VERSION 5.7 ;
BUSBITCHARS "[]" ;
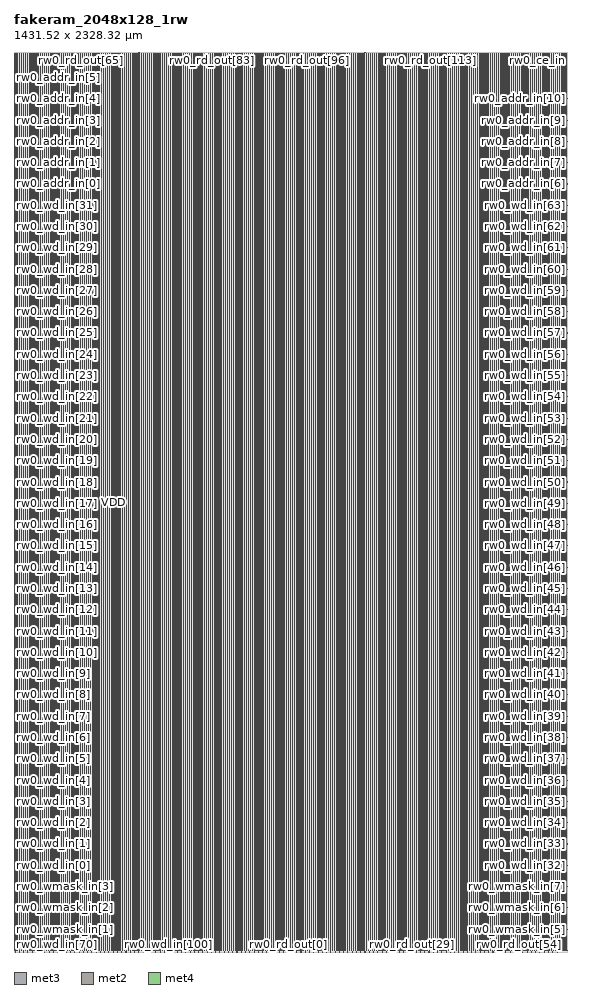
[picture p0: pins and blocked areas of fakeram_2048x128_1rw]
MACRO fakeram_2048x128_1rw
  FOREIGN fakeram_2048x128_1rw 0 0 ;
  SYMMETRY X Y R90 ;
  SIZE 1431.520 BY 2328.320 ;
  CLASS BLOCK ;
  PIN rw0_wmask_in[0]
    DIRECTION INPUT ;
    USE SIGNAL ;
    SHAPE ABUTMENT ;
    PORT
      LAYER met3 ;
      RECT 0.000 3.930 0.900 4.230 ;
    END
  END rw0_wmask_in[0]
  PIN rw0_wmask_in[1]
    DIRECTION INPUT ;
    USE SIGNAL ;
    SHAPE ABUTMENT ;
    PORT
      LAYER met3 ;
      RECT 0.000 59.010 0.900 59.310 ;
    END
  END rw0_wmask_in[1]
  PIN rw0_wmask_in[2]
    DIRECTION INPUT ;
    USE SIGNAL ;
    SHAPE ABUTMENT ;
    PORT
      LAYER met3 ;
      RECT 0.000 114.090 0.900 114.390 ;
    END
  END rw0_wmask_in[2]
  PIN rw0_wmask_in[3]
    DIRECTION INPUT ;
    USE SIGNAL ;
    SHAPE ABUTMENT ;
    PORT
      LAYER met3 ;
      RECT 0.000 169.170 0.900 169.470 ;
    END
  END rw0_wmask_in[3]
  PIN rw0_wmask_in[4]
    DIRECTION INPUT ;
    USE SIGNAL ;
    SHAPE ABUTMENT ;
    PORT
      LAYER met3 ;
      RECT 1430.620 3.930 1431.520 4.230 ;
    END
  END rw0_wmask_in[4]
  PIN rw0_wmask_in[5]
    DIRECTION INPUT ;
    USE SIGNAL ;
    SHAPE ABUTMENT ;
    PORT
      LAYER met3 ;
      RECT 1430.620 59.010 1431.520 59.310 ;
    END
  END rw0_wmask_in[5]
  PIN rw0_wmask_in[6]
    DIRECTION INPUT ;
    USE SIGNAL ;
    SHAPE ABUTMENT ;
    PORT
      LAYER met3 ;
      RECT 1430.620 114.090 1431.520 114.390 ;
    END
  END rw0_wmask_in[6]
  PIN rw0_wmask_in[7]
    DIRECTION INPUT ;
    USE SIGNAL ;
    SHAPE ABUTMENT ;
    PORT
      LAYER met3 ;
      RECT 1430.620 169.170 1431.520 169.470 ;
    END
  END rw0_wmask_in[7]
  PIN rw0_wmask_in[8]
    DIRECTION INPUT ;
    USE SIGNAL ;
    SHAPE ABUTMENT ;
    PORT
      LAYER met2 ;
      RECT 2.690 2327.900 2.830 2328.320 ;
    END
  END rw0_wmask_in[8]
  PIN rw0_wmask_in[9]
    DIRECTION INPUT ;
    USE SIGNAL ;
    SHAPE ABUTMENT ;
    PORT
      LAYER met2 ;
      RECT 21.550 2327.900 21.690 2328.320 ;
    END
  END rw0_wmask_in[9]
  PIN rw0_wmask_in[10]
    DIRECTION INPUT ;
    USE SIGNAL ;
    SHAPE ABUTMENT ;
    PORT
      LAYER met2 ;
      RECT 40.410 2327.900 40.550 2328.320 ;
    END
  END rw0_wmask_in[10]
  PIN rw0_wmask_in[11]
    DIRECTION INPUT ;
    USE SIGNAL ;
    SHAPE ABUTMENT ;
    PORT
      LAYER met2 ;
      RECT 59.270 2327.900 59.410 2328.320 ;
    END
  END rw0_wmask_in[11]
  PIN rw0_wmask_in[12]
    DIRECTION INPUT ;
    USE SIGNAL ;
    SHAPE ABUTMENT ;
    PORT
      LAYER met2 ;
      RECT 78.130 2327.900 78.270 2328.320 ;
    END
  END rw0_wmask_in[12]
  PIN rw0_wmask_in[13]
    DIRECTION INPUT ;
    USE SIGNAL ;
    SHAPE ABUTMENT ;
    PORT
      LAYER met2 ;
      RECT 96.990 2327.900 97.130 2328.320 ;
    END
  END rw0_wmask_in[13]
  PIN rw0_wmask_in[14]
    DIRECTION INPUT ;
    USE SIGNAL ;
    SHAPE ABUTMENT ;
    PORT
      LAYER met2 ;
      RECT 115.850 2327.900 115.990 2328.320 ;
    END
  END rw0_wmask_in[14]
  PIN rw0_wmask_in[15]
    DIRECTION INPUT ;
    USE SIGNAL ;
    SHAPE ABUTMENT ;
    PORT
      LAYER met2 ;
      RECT 134.710 2327.900 134.850 2328.320 ;
    END
  END rw0_wmask_in[15]
  PIN rw0_wd_in[0]
    DIRECTION INPUT ;
    USE SIGNAL ;
    SHAPE ABUTMENT ;
    PORT
      LAYER met3 ;
      RECT 0.000 224.250 0.900 224.550 ;
    END
  END rw0_wd_in[0]
  PIN rw0_wd_in[1]
    DIRECTION INPUT ;
    USE SIGNAL ;
    SHAPE ABUTMENT ;
    PORT
      LAYER met3 ;
      RECT 0.000 279.330 0.900 279.630 ;
    END
  END rw0_wd_in[1]
  PIN rw0_wd_in[2]
    DIRECTION INPUT ;
    USE SIGNAL ;
    SHAPE ABUTMENT ;
    PORT
      LAYER met3 ;
      RECT 0.000 334.410 0.900 334.710 ;
    END
  END rw0_wd_in[2]
  PIN rw0_wd_in[3]
    DIRECTION INPUT ;
    USE SIGNAL ;
    SHAPE ABUTMENT ;
    PORT
      LAYER met3 ;
      RECT 0.000 389.490 0.900 389.790 ;
    END
  END rw0_wd_in[3]
  PIN rw0_wd_in[4]
    DIRECTION INPUT ;
    USE SIGNAL ;
    SHAPE ABUTMENT ;
    PORT
      LAYER met3 ;
      RECT 0.000 444.570 0.900 444.870 ;
    END
  END rw0_wd_in[4]
  PIN rw0_wd_in[5]
    DIRECTION INPUT ;
    USE SIGNAL ;
    SHAPE ABUTMENT ;
    PORT
      LAYER met3 ;
      RECT 0.000 499.650 0.900 499.950 ;
    END
  END rw0_wd_in[5]
  PIN rw0_wd_in[6]
    DIRECTION INPUT ;
    USE SIGNAL ;
    SHAPE ABUTMENT ;
    PORT
      LAYER met3 ;
      RECT 0.000 554.730 0.900 555.030 ;
    END
  END rw0_wd_in[6]
  PIN rw0_wd_in[7]
    DIRECTION INPUT ;
    USE SIGNAL ;
    SHAPE ABUTMENT ;
    PORT
      LAYER met3 ;
      RECT 0.000 609.810 0.900 610.110 ;
    END
  END rw0_wd_in[7]
  PIN rw0_wd_in[8]
    DIRECTION INPUT ;
    USE SIGNAL ;
    SHAPE ABUTMENT ;
    PORT
      LAYER met3 ;
      RECT 0.000 664.890 0.900 665.190 ;
    END
  END rw0_wd_in[8]
  PIN rw0_wd_in[9]
    DIRECTION INPUT ;
    USE SIGNAL ;
    SHAPE ABUTMENT ;
    PORT
      LAYER met3 ;
      RECT 0.000 719.970 0.900 720.270 ;
    END
  END rw0_wd_in[9]
  PIN rw0_wd_in[10]
    DIRECTION INPUT ;
    USE SIGNAL ;
    SHAPE ABUTMENT ;
    PORT
      LAYER met3 ;
      RECT 0.000 775.050 0.900 775.350 ;
    END
  END rw0_wd_in[10]
  PIN rw0_wd_in[11]
    DIRECTION INPUT ;
    USE SIGNAL ;
    SHAPE ABUTMENT ;
    PORT
      LAYER met3 ;
      RECT 0.000 830.130 0.900 830.430 ;
    END
  END rw0_wd_in[11]
  PIN rw0_wd_in[12]
    DIRECTION INPUT ;
    USE SIGNAL ;
    SHAPE ABUTMENT ;
    PORT
      LAYER met3 ;
      RECT 0.000 885.210 0.900 885.510 ;
    END
  END rw0_wd_in[12]
  PIN rw0_wd_in[13]
    DIRECTION INPUT ;
    USE SIGNAL ;
    SHAPE ABUTMENT ;
    PORT
      LAYER met3 ;
      RECT 0.000 940.290 0.900 940.590 ;
    END
  END rw0_wd_in[13]
  PIN rw0_wd_in[14]
    DIRECTION INPUT ;
    USE SIGNAL ;
    SHAPE ABUTMENT ;
    PORT
      LAYER met3 ;
      RECT 0.000 995.370 0.900 995.670 ;
    END
  END rw0_wd_in[14]
  PIN rw0_wd_in[15]
    DIRECTION INPUT ;
    USE SIGNAL ;
    SHAPE ABUTMENT ;
    PORT
      LAYER met3 ;
      RECT 0.000 1050.450 0.900 1050.750 ;
    END
  END rw0_wd_in[15]
  PIN rw0_wd_in[16]
    DIRECTION INPUT ;
    USE SIGNAL ;
    SHAPE ABUTMENT ;
    PORT
      LAYER met3 ;
      RECT 0.000 1105.530 0.900 1105.830 ;
    END
  END rw0_wd_in[16]
  PIN rw0_wd_in[17]
    DIRECTION INPUT ;
    USE SIGNAL ;
    SHAPE ABUTMENT ;
    PORT
      LAYER met3 ;
      RECT 0.000 1160.610 0.900 1160.910 ;
    END
  END rw0_wd_in[17]
  PIN rw0_wd_in[18]
    DIRECTION INPUT ;
    USE SIGNAL ;
    SHAPE ABUTMENT ;
    PORT
      LAYER met3 ;
      RECT 0.000 1215.690 0.900 1215.990 ;
    END
  END rw0_wd_in[18]
  PIN rw0_wd_in[19]
    DIRECTION INPUT ;
    USE SIGNAL ;
    SHAPE ABUTMENT ;
    PORT
      LAYER met3 ;
      RECT 0.000 1270.770 0.900 1271.070 ;
    END
  END rw0_wd_in[19]
  PIN rw0_wd_in[20]
    DIRECTION INPUT ;
    USE SIGNAL ;
    SHAPE ABUTMENT ;
    PORT
      LAYER met3 ;
      RECT 0.000 1325.850 0.900 1326.150 ;
    END
  END rw0_wd_in[20]
  PIN rw0_wd_in[21]
    DIRECTION INPUT ;
    USE SIGNAL ;
    SHAPE ABUTMENT ;
    PORT
      LAYER met3 ;
      RECT 0.000 1380.930 0.900 1381.230 ;
    END
  END rw0_wd_in[21]
  PIN rw0_wd_in[22]
    DIRECTION INPUT ;
    USE SIGNAL ;
    SHAPE ABUTMENT ;
    PORT
      LAYER met3 ;
      RECT 0.000 1436.010 0.900 1436.310 ;
    END
  END rw0_wd_in[22]
  PIN rw0_wd_in[23]
    DIRECTION INPUT ;
    USE SIGNAL ;
    SHAPE ABUTMENT ;
    PORT
      LAYER met3 ;
      RECT 0.000 1491.090 0.900 1491.390 ;
    END
  END rw0_wd_in[23]
  PIN rw0_wd_in[24]
    DIRECTION INPUT ;
    USE SIGNAL ;
    SHAPE ABUTMENT ;
    PORT
      LAYER met3 ;
      RECT 0.000 1546.170 0.900 1546.470 ;
    END
  END rw0_wd_in[24]
  PIN rw0_wd_in[25]
    DIRECTION INPUT ;
    USE SIGNAL ;
    SHAPE ABUTMENT ;
    PORT
      LAYER met3 ;
      RECT 0.000 1601.250 0.900 1601.550 ;
    END
  END rw0_wd_in[25]
  PIN rw0_wd_in[26]
    DIRECTION INPUT ;
    USE SIGNAL ;
    SHAPE ABUTMENT ;
    PORT
      LAYER met3 ;
      RECT 0.000 1656.330 0.900 1656.630 ;
    END
  END rw0_wd_in[26]
  PIN rw0_wd_in[27]
    DIRECTION INPUT ;
    USE SIGNAL ;
    SHAPE ABUTMENT ;
    PORT
      LAYER met3 ;
      RECT 0.000 1711.410 0.900 1711.710 ;
    END
  END rw0_wd_in[27]
  PIN rw0_wd_in[28]
    DIRECTION INPUT ;
    USE SIGNAL ;
    SHAPE ABUTMENT ;
    PORT
      LAYER met3 ;
      RECT 0.000 1766.490 0.900 1766.790 ;
    END
  END rw0_wd_in[28]
  PIN rw0_wd_in[29]
    DIRECTION INPUT ;
    USE SIGNAL ;
    SHAPE ABUTMENT ;
    PORT
      LAYER met3 ;
      RECT 0.000 1821.570 0.900 1821.870 ;
    END
  END rw0_wd_in[29]
  PIN rw0_wd_in[30]
    DIRECTION INPUT ;
    USE SIGNAL ;
    SHAPE ABUTMENT ;
    PORT
      LAYER met3 ;
      RECT 0.000 1876.650 0.900 1876.950 ;
    END
  END rw0_wd_in[30]
  PIN rw0_wd_in[31]
    DIRECTION INPUT ;
    USE SIGNAL ;
    SHAPE ABUTMENT ;
    PORT
      LAYER met3 ;
      RECT 0.000 1931.730 0.900 1932.030 ;
    END
  END rw0_wd_in[31]
  PIN rw0_wd_in[32]
    DIRECTION INPUT ;
    USE SIGNAL ;
    SHAPE ABUTMENT ;
    PORT
      LAYER met3 ;
      RECT 1430.620 224.250 1431.520 224.550 ;
    END
  END rw0_wd_in[32]
  PIN rw0_wd_in[33]
    DIRECTION INPUT ;
    USE SIGNAL ;
    SHAPE ABUTMENT ;
    PORT
      LAYER met3 ;
      RECT 1430.620 279.330 1431.520 279.630 ;
    END
  END rw0_wd_in[33]
  PIN rw0_wd_in[34]
    DIRECTION INPUT ;
    USE SIGNAL ;
    SHAPE ABUTMENT ;
    PORT
      LAYER met3 ;
      RECT 1430.620 334.410 1431.520 334.710 ;
    END
  END rw0_wd_in[34]
  PIN rw0_wd_in[35]
    DIRECTION INPUT ;
    USE SIGNAL ;
    SHAPE ABUTMENT ;
    PORT
      LAYER met3 ;
      RECT 1430.620 389.490 1431.520 389.790 ;
    END
  END rw0_wd_in[35]
  PIN rw0_wd_in[36]
    DIRECTION INPUT ;
    USE SIGNAL ;
    SHAPE ABUTMENT ;
    PORT
      LAYER met3 ;
      RECT 1430.620 444.570 1431.520 444.870 ;
    END
  END rw0_wd_in[36]
  PIN rw0_wd_in[37]
    DIRECTION INPUT ;
    USE SIGNAL ;
    SHAPE ABUTMENT ;
    PORT
      LAYER met3 ;
      RECT 1430.620 499.650 1431.520 499.950 ;
    END
  END rw0_wd_in[37]
  PIN rw0_wd_in[38]
    DIRECTION INPUT ;
    USE SIGNAL ;
    SHAPE ABUTMENT ;
    PORT
      LAYER met3 ;
      RECT 1430.620 554.730 1431.520 555.030 ;
    END
  END rw0_wd_in[38]
  PIN rw0_wd_in[39]
    DIRECTION INPUT ;
    USE SIGNAL ;
    SHAPE ABUTMENT ;
    PORT
      LAYER met3 ;
      RECT 1430.620 609.810 1431.520 610.110 ;
    END
  END rw0_wd_in[39]
  PIN rw0_wd_in[40]
    DIRECTION INPUT ;
    USE SIGNAL ;
    SHAPE ABUTMENT ;
    PORT
      LAYER met3 ;
      RECT 1430.620 664.890 1431.520 665.190 ;
    END
  END rw0_wd_in[40]
  PIN rw0_wd_in[41]
    DIRECTION INPUT ;
    USE SIGNAL ;
    SHAPE ABUTMENT ;
    PORT
      LAYER met3 ;
      RECT 1430.620 719.970 1431.520 720.270 ;
    END
  END rw0_wd_in[41]
  PIN rw0_wd_in[42]
    DIRECTION INPUT ;
    USE SIGNAL ;
    SHAPE ABUTMENT ;
    PORT
      LAYER met3 ;
      RECT 1430.620 775.050 1431.520 775.350 ;
    END
  END rw0_wd_in[42]
  PIN rw0_wd_in[43]
    DIRECTION INPUT ;
    USE SIGNAL ;
    SHAPE ABUTMENT ;
    PORT
      LAYER met3 ;
      RECT 1430.620 830.130 1431.520 830.430 ;
    END
  END rw0_wd_in[43]
  PIN rw0_wd_in[44]
    DIRECTION INPUT ;
    USE SIGNAL ;
    SHAPE ABUTMENT ;
    PORT
      LAYER met3 ;
      RECT 1430.620 885.210 1431.520 885.510 ;
    END
  END rw0_wd_in[44]
  PIN rw0_wd_in[45]
    DIRECTION INPUT ;
    USE SIGNAL ;
    SHAPE ABUTMENT ;
    PORT
      LAYER met3 ;
      RECT 1430.620 940.290 1431.520 940.590 ;
    END
  END rw0_wd_in[45]
  PIN rw0_wd_in[46]
    DIRECTION INPUT ;
    USE SIGNAL ;
    SHAPE ABUTMENT ;
    PORT
      LAYER met3 ;
      RECT 1430.620 995.370 1431.520 995.670 ;
    END
  END rw0_wd_in[46]
  PIN rw0_wd_in[47]
    DIRECTION INPUT ;
    USE SIGNAL ;
    SHAPE ABUTMENT ;
    PORT
      LAYER met3 ;
      RECT 1430.620 1050.450 1431.520 1050.750 ;
    END
  END rw0_wd_in[47]
  PIN rw0_wd_in[48]
    DIRECTION INPUT ;
    USE SIGNAL ;
    SHAPE ABUTMENT ;
    PORT
      LAYER met3 ;
      RECT 1430.620 1105.530 1431.520 1105.830 ;
    END
  END rw0_wd_in[48]
  PIN rw0_wd_in[49]
    DIRECTION INPUT ;
    USE SIGNAL ;
    SHAPE ABUTMENT ;
    PORT
      LAYER met3 ;
      RECT 1430.620 1160.610 1431.520 1160.910 ;
    END
  END rw0_wd_in[49]
  PIN rw0_wd_in[50]
    DIRECTION INPUT ;
    USE SIGNAL ;
    SHAPE ABUTMENT ;
    PORT
      LAYER met3 ;
      RECT 1430.620 1215.690 1431.520 1215.990 ;
    END
  END rw0_wd_in[50]
  PIN rw0_wd_in[51]
    DIRECTION INPUT ;
    USE SIGNAL ;
    SHAPE ABUTMENT ;
    PORT
      LAYER met3 ;
      RECT 1430.620 1270.770 1431.520 1271.070 ;
    END
  END rw0_wd_in[51]
  PIN rw0_wd_in[52]
    DIRECTION INPUT ;
    USE SIGNAL ;
    SHAPE ABUTMENT ;
    PORT
      LAYER met3 ;
      RECT 1430.620 1325.850 1431.520 1326.150 ;
    END
  END rw0_wd_in[52]
  PIN rw0_wd_in[53]
    DIRECTION INPUT ;
    USE SIGNAL ;
    SHAPE ABUTMENT ;
    PORT
      LAYER met3 ;
      RECT 1430.620 1380.930 1431.520 1381.230 ;
    END
  END rw0_wd_in[53]
  PIN rw0_wd_in[54]
    DIRECTION INPUT ;
    USE SIGNAL ;
    SHAPE ABUTMENT ;
    PORT
      LAYER met3 ;
      RECT 1430.620 1436.010 1431.520 1436.310 ;
    END
  END rw0_wd_in[54]
  PIN rw0_wd_in[55]
    DIRECTION INPUT ;
    USE SIGNAL ;
    SHAPE ABUTMENT ;
    PORT
      LAYER met3 ;
      RECT 1430.620 1491.090 1431.520 1491.390 ;
    END
  END rw0_wd_in[55]
  PIN rw0_wd_in[56]
    DIRECTION INPUT ;
    USE SIGNAL ;
    SHAPE ABUTMENT ;
    PORT
      LAYER met3 ;
      RECT 1430.620 1546.170 1431.520 1546.470 ;
    END
  END rw0_wd_in[56]
  PIN rw0_wd_in[57]
    DIRECTION INPUT ;
    USE SIGNAL ;
    SHAPE ABUTMENT ;
    PORT
      LAYER met3 ;
      RECT 1430.620 1601.250 1431.520 1601.550 ;
    END
  END rw0_wd_in[57]
  PIN rw0_wd_in[58]
    DIRECTION INPUT ;
    USE SIGNAL ;
    SHAPE ABUTMENT ;
    PORT
      LAYER met3 ;
      RECT 1430.620 1656.330 1431.520 1656.630 ;
    END
  END rw0_wd_in[58]
  PIN rw0_wd_in[59]
    DIRECTION INPUT ;
    USE SIGNAL ;
    SHAPE ABUTMENT ;
    PORT
      LAYER met3 ;
      RECT 1430.620 1711.410 1431.520 1711.710 ;
    END
  END rw0_wd_in[59]
  PIN rw0_wd_in[60]
    DIRECTION INPUT ;
    USE SIGNAL ;
    SHAPE ABUTMENT ;
    PORT
      LAYER met3 ;
      RECT 1430.620 1766.490 1431.520 1766.790 ;
    END
  END rw0_wd_in[60]
  PIN rw0_wd_in[61]
    DIRECTION INPUT ;
    USE SIGNAL ;
    SHAPE ABUTMENT ;
    PORT
      LAYER met3 ;
      RECT 1430.620 1821.570 1431.520 1821.870 ;
    END
  END rw0_wd_in[61]
  PIN rw0_wd_in[62]
    DIRECTION INPUT ;
    USE SIGNAL ;
    SHAPE ABUTMENT ;
    PORT
      LAYER met3 ;
      RECT 1430.620 1876.650 1431.520 1876.950 ;
    END
  END rw0_wd_in[62]
  PIN rw0_wd_in[63]
    DIRECTION INPUT ;
    USE SIGNAL ;
    SHAPE ABUTMENT ;
    PORT
      LAYER met3 ;
      RECT 1430.620 1931.730 1431.520 1932.030 ;
    END
  END rw0_wd_in[63]
  PIN rw0_wd_in[64]
    DIRECTION INPUT ;
    USE SIGNAL ;
    SHAPE ABUTMENT ;
    PORT
      LAYER met2 ;
      RECT 2.690 0.000 2.830 0.420 ;
    END
  END rw0_wd_in[64]
  PIN rw0_wd_in[65]
    DIRECTION INPUT ;
    USE SIGNAL ;
    SHAPE ABUTMENT ;
    PORT
      LAYER met2 ;
      RECT 13.730 0.000 13.870 0.420 ;
    END
  END rw0_wd_in[65]
  PIN rw0_wd_in[66]
    DIRECTION INPUT ;
    USE SIGNAL ;
    SHAPE ABUTMENT ;
    PORT
      LAYER met2 ;
      RECT 24.770 0.000 24.910 0.420 ;
    END
  END rw0_wd_in[66]
  PIN rw0_wd_in[67]
    DIRECTION INPUT ;
    USE SIGNAL ;
    SHAPE ABUTMENT ;
    PORT
      LAYER met2 ;
      RECT 35.810 0.000 35.950 0.420 ;
    END
  END rw0_wd_in[67]
  PIN rw0_wd_in[68]
    DIRECTION INPUT ;
    USE SIGNAL ;
    SHAPE ABUTMENT ;
    PORT
      LAYER met2 ;
      RECT 46.850 0.000 46.990 0.420 ;
    END
  END rw0_wd_in[68]
  PIN rw0_wd_in[69]
    DIRECTION INPUT ;
    USE SIGNAL ;
    SHAPE ABUTMENT ;
    PORT
      LAYER met2 ;
      RECT 57.890 0.000 58.030 0.420 ;
    END
  END rw0_wd_in[69]
  PIN rw0_wd_in[70]
    DIRECTION INPUT ;
    USE SIGNAL ;
    SHAPE ABUTMENT ;
    PORT
      LAYER met2 ;
      RECT 68.930 0.000 69.070 0.420 ;
    END
  END rw0_wd_in[70]
  PIN rw0_wd_in[71]
    DIRECTION INPUT ;
    USE SIGNAL ;
    SHAPE ABUTMENT ;
    PORT
      LAYER met2 ;
      RECT 79.970 0.000 80.110 0.420 ;
    END
  END rw0_wd_in[71]
  PIN rw0_wd_in[72]
    DIRECTION INPUT ;
    USE SIGNAL ;
    SHAPE ABUTMENT ;
    PORT
      LAYER met2 ;
      RECT 91.010 0.000 91.150 0.420 ;
    END
  END rw0_wd_in[72]
  PIN rw0_wd_in[73]
    DIRECTION INPUT ;
    USE SIGNAL ;
    SHAPE ABUTMENT ;
    PORT
      LAYER met2 ;
      RECT 102.050 0.000 102.190 0.420 ;
    END
  END rw0_wd_in[73]
  PIN rw0_wd_in[74]
    DIRECTION INPUT ;
    USE SIGNAL ;
    SHAPE ABUTMENT ;
    PORT
      LAYER met2 ;
      RECT 113.090 0.000 113.230 0.420 ;
    END
  END rw0_wd_in[74]
  PIN rw0_wd_in[75]
    DIRECTION INPUT ;
    USE SIGNAL ;
    SHAPE ABUTMENT ;
    PORT
      LAYER met2 ;
      RECT 124.130 0.000 124.270 0.420 ;
    END
  END rw0_wd_in[75]
  PIN rw0_wd_in[76]
    DIRECTION INPUT ;
    USE SIGNAL ;
    SHAPE ABUTMENT ;
    PORT
      LAYER met2 ;
      RECT 135.170 0.000 135.310 0.420 ;
    END
  END rw0_wd_in[76]
  PIN rw0_wd_in[77]
    DIRECTION INPUT ;
    USE SIGNAL ;
    SHAPE ABUTMENT ;
    PORT
      LAYER met2 ;
      RECT 146.210 0.000 146.350 0.420 ;
    END
  END rw0_wd_in[77]
  PIN rw0_wd_in[78]
    DIRECTION INPUT ;
    USE SIGNAL ;
    SHAPE ABUTMENT ;
    PORT
      LAYER met2 ;
      RECT 157.250 0.000 157.390 0.420 ;
    END
  END rw0_wd_in[78]
  PIN rw0_wd_in[79]
    DIRECTION INPUT ;
    USE SIGNAL ;
    SHAPE ABUTMENT ;
    PORT
      LAYER met2 ;
      RECT 168.290 0.000 168.430 0.420 ;
    END
  END rw0_wd_in[79]
  PIN rw0_wd_in[80]
    DIRECTION INPUT ;
    USE SIGNAL ;
    SHAPE ABUTMENT ;
    PORT
      LAYER met2 ;
      RECT 179.330 0.000 179.470 0.420 ;
    END
  END rw0_wd_in[80]
  PIN rw0_wd_in[81]
    DIRECTION INPUT ;
    USE SIGNAL ;
    SHAPE ABUTMENT ;
    PORT
      LAYER met2 ;
      RECT 190.370 0.000 190.510 0.420 ;
    END
  END rw0_wd_in[81]
  PIN rw0_wd_in[82]
    DIRECTION INPUT ;
    USE SIGNAL ;
    SHAPE ABUTMENT ;
    PORT
      LAYER met2 ;
      RECT 201.410 0.000 201.550 0.420 ;
    END
  END rw0_wd_in[82]
  PIN rw0_wd_in[83]
    DIRECTION INPUT ;
    USE SIGNAL ;
    SHAPE ABUTMENT ;
    PORT
      LAYER met2 ;
      RECT 212.450 0.000 212.590 0.420 ;
    END
  END rw0_wd_in[83]
  PIN rw0_wd_in[84]
    DIRECTION INPUT ;
    USE SIGNAL ;
    SHAPE ABUTMENT ;
    PORT
      LAYER met2 ;
      RECT 223.490 0.000 223.630 0.420 ;
    END
  END rw0_wd_in[84]
  PIN rw0_wd_in[85]
    DIRECTION INPUT ;
    USE SIGNAL ;
    SHAPE ABUTMENT ;
    PORT
      LAYER met2 ;
      RECT 234.530 0.000 234.670 0.420 ;
    END
  END rw0_wd_in[85]
  PIN rw0_wd_in[86]
    DIRECTION INPUT ;
    USE SIGNAL ;
    SHAPE ABUTMENT ;
    PORT
      LAYER met2 ;
      RECT 245.570 0.000 245.710 0.420 ;
    END
  END rw0_wd_in[86]
  PIN rw0_wd_in[87]
    DIRECTION INPUT ;
    USE SIGNAL ;
    SHAPE ABUTMENT ;
    PORT
      LAYER met2 ;
      RECT 256.610 0.000 256.750 0.420 ;
    END
  END rw0_wd_in[87]
  PIN rw0_wd_in[88]
    DIRECTION INPUT ;
    USE SIGNAL ;
    SHAPE ABUTMENT ;
    PORT
      LAYER met2 ;
      RECT 267.650 0.000 267.790 0.420 ;
    END
  END rw0_wd_in[88]
  PIN rw0_wd_in[89]
    DIRECTION INPUT ;
    USE SIGNAL ;
    SHAPE ABUTMENT ;
    PORT
      LAYER met2 ;
      RECT 278.690 0.000 278.830 0.420 ;
    END
  END rw0_wd_in[89]
  PIN rw0_wd_in[90]
    DIRECTION INPUT ;
    USE SIGNAL ;
    SHAPE ABUTMENT ;
    PORT
      LAYER met2 ;
      RECT 289.730 0.000 289.870 0.420 ;
    END
  END rw0_wd_in[90]
  PIN rw0_wd_in[91]
    DIRECTION INPUT ;
    USE SIGNAL ;
    SHAPE ABUTMENT ;
    PORT
      LAYER met2 ;
      RECT 300.770 0.000 300.910 0.420 ;
    END
  END rw0_wd_in[91]
  PIN rw0_wd_in[92]
    DIRECTION INPUT ;
    USE SIGNAL ;
    SHAPE ABUTMENT ;
    PORT
      LAYER met2 ;
      RECT 311.810 0.000 311.950 0.420 ;
    END
  END rw0_wd_in[92]
  PIN rw0_wd_in[93]
    DIRECTION INPUT ;
    USE SIGNAL ;
    SHAPE ABUTMENT ;
    PORT
      LAYER met2 ;
      RECT 322.850 0.000 322.990 0.420 ;
    END
  END rw0_wd_in[93]
  PIN rw0_wd_in[94]
    DIRECTION INPUT ;
    USE SIGNAL ;
    SHAPE ABUTMENT ;
    PORT
      LAYER met2 ;
      RECT 333.890 0.000 334.030 0.420 ;
    END
  END rw0_wd_in[94]
  PIN rw0_wd_in[95]
    DIRECTION INPUT ;
    USE SIGNAL ;
    SHAPE ABUTMENT ;
    PORT
      LAYER met2 ;
      RECT 344.930 0.000 345.070 0.420 ;
    END
  END rw0_wd_in[95]
  PIN rw0_wd_in[96]
    DIRECTION INPUT ;
    USE SIGNAL ;
    SHAPE ABUTMENT ;
    PORT
      LAYER met2 ;
      RECT 355.970 0.000 356.110 0.420 ;
    END
  END rw0_wd_in[96]
  PIN rw0_wd_in[97]
    DIRECTION INPUT ;
    USE SIGNAL ;
    SHAPE ABUTMENT ;
    PORT
      LAYER met2 ;
      RECT 367.010 0.000 367.150 0.420 ;
    END
  END rw0_wd_in[97]
  PIN rw0_wd_in[98]
    DIRECTION INPUT ;
    USE SIGNAL ;
    SHAPE ABUTMENT ;
    PORT
      LAYER met2 ;
      RECT 378.050 0.000 378.190 0.420 ;
    END
  END rw0_wd_in[98]
  PIN rw0_wd_in[99]
    DIRECTION INPUT ;
    USE SIGNAL ;
    SHAPE ABUTMENT ;
    PORT
      LAYER met2 ;
      RECT 389.090 0.000 389.230 0.420 ;
    END
  END rw0_wd_in[99]
  PIN rw0_wd_in[100]
    DIRECTION INPUT ;
    USE SIGNAL ;
    SHAPE ABUTMENT ;
    PORT
      LAYER met2 ;
      RECT 400.130 0.000 400.270 0.420 ;
    END
  END rw0_wd_in[100]
  PIN rw0_wd_in[101]
    DIRECTION INPUT ;
    USE SIGNAL ;
    SHAPE ABUTMENT ;
    PORT
      LAYER met2 ;
      RECT 411.170 0.000 411.310 0.420 ;
    END
  END rw0_wd_in[101]
  PIN rw0_wd_in[102]
    DIRECTION INPUT ;
    USE SIGNAL ;
    SHAPE ABUTMENT ;
    PORT
      LAYER met2 ;
      RECT 422.210 0.000 422.350 0.420 ;
    END
  END rw0_wd_in[102]
  PIN rw0_wd_in[103]
    DIRECTION INPUT ;
    USE SIGNAL ;
    SHAPE ABUTMENT ;
    PORT
      LAYER met2 ;
      RECT 433.250 0.000 433.390 0.420 ;
    END
  END rw0_wd_in[103]
  PIN rw0_wd_in[104]
    DIRECTION INPUT ;
    USE SIGNAL ;
    SHAPE ABUTMENT ;
    PORT
      LAYER met2 ;
      RECT 444.290 0.000 444.430 0.420 ;
    END
  END rw0_wd_in[104]
  PIN rw0_wd_in[105]
    DIRECTION INPUT ;
    USE SIGNAL ;
    SHAPE ABUTMENT ;
    PORT
      LAYER met2 ;
      RECT 455.330 0.000 455.470 0.420 ;
    END
  END rw0_wd_in[105]
  PIN rw0_wd_in[106]
    DIRECTION INPUT ;
    USE SIGNAL ;
    SHAPE ABUTMENT ;
    PORT
      LAYER met2 ;
      RECT 466.370 0.000 466.510 0.420 ;
    END
  END rw0_wd_in[106]
  PIN rw0_wd_in[107]
    DIRECTION INPUT ;
    USE SIGNAL ;
    SHAPE ABUTMENT ;
    PORT
      LAYER met2 ;
      RECT 477.410 0.000 477.550 0.420 ;
    END
  END rw0_wd_in[107]
  PIN rw0_wd_in[108]
    DIRECTION INPUT ;
    USE SIGNAL ;
    SHAPE ABUTMENT ;
    PORT
      LAYER met2 ;
      RECT 488.450 0.000 488.590 0.420 ;
    END
  END rw0_wd_in[108]
  PIN rw0_wd_in[109]
    DIRECTION INPUT ;
    USE SIGNAL ;
    SHAPE ABUTMENT ;
    PORT
      LAYER met2 ;
      RECT 499.490 0.000 499.630 0.420 ;
    END
  END rw0_wd_in[109]
  PIN rw0_wd_in[110]
    DIRECTION INPUT ;
    USE SIGNAL ;
    SHAPE ABUTMENT ;
    PORT
      LAYER met2 ;
      RECT 510.530 0.000 510.670 0.420 ;
    END
  END rw0_wd_in[110]
  PIN rw0_wd_in[111]
    DIRECTION INPUT ;
    USE SIGNAL ;
    SHAPE ABUTMENT ;
    PORT
      LAYER met2 ;
      RECT 521.570 0.000 521.710 0.420 ;
    END
  END rw0_wd_in[111]
  PIN rw0_wd_in[112]
    DIRECTION INPUT ;
    USE SIGNAL ;
    SHAPE ABUTMENT ;
    PORT
      LAYER met2 ;
      RECT 532.610 0.000 532.750 0.420 ;
    END
  END rw0_wd_in[112]
  PIN rw0_wd_in[113]
    DIRECTION INPUT ;
    USE SIGNAL ;
    SHAPE ABUTMENT ;
    PORT
      LAYER met2 ;
      RECT 543.650 0.000 543.790 0.420 ;
    END
  END rw0_wd_in[113]
  PIN rw0_wd_in[114]
    DIRECTION INPUT ;
    USE SIGNAL ;
    SHAPE ABUTMENT ;
    PORT
      LAYER met2 ;
      RECT 554.690 0.000 554.830 0.420 ;
    END
  END rw0_wd_in[114]
  PIN rw0_wd_in[115]
    DIRECTION INPUT ;
    USE SIGNAL ;
    SHAPE ABUTMENT ;
    PORT
      LAYER met2 ;
      RECT 565.730 0.000 565.870 0.420 ;
    END
  END rw0_wd_in[115]
  PIN rw0_wd_in[116]
    DIRECTION INPUT ;
    USE SIGNAL ;
    SHAPE ABUTMENT ;
    PORT
      LAYER met2 ;
      RECT 576.770 0.000 576.910 0.420 ;
    END
  END rw0_wd_in[116]
  PIN rw0_wd_in[117]
    DIRECTION INPUT ;
    USE SIGNAL ;
    SHAPE ABUTMENT ;
    PORT
      LAYER met2 ;
      RECT 587.810 0.000 587.950 0.420 ;
    END
  END rw0_wd_in[117]
  PIN rw0_wd_in[118]
    DIRECTION INPUT ;
    USE SIGNAL ;
    SHAPE ABUTMENT ;
    PORT
      LAYER met2 ;
      RECT 598.850 0.000 598.990 0.420 ;
    END
  END rw0_wd_in[118]
  PIN rw0_wd_in[119]
    DIRECTION INPUT ;
    USE SIGNAL ;
    SHAPE ABUTMENT ;
    PORT
      LAYER met2 ;
      RECT 609.890 0.000 610.030 0.420 ;
    END
  END rw0_wd_in[119]
  PIN rw0_wd_in[120]
    DIRECTION INPUT ;
    USE SIGNAL ;
    SHAPE ABUTMENT ;
    PORT
      LAYER met2 ;
      RECT 620.930 0.000 621.070 0.420 ;
    END
  END rw0_wd_in[120]
  PIN rw0_wd_in[121]
    DIRECTION INPUT ;
    USE SIGNAL ;
    SHAPE ABUTMENT ;
    PORT
      LAYER met2 ;
      RECT 631.970 0.000 632.110 0.420 ;
    END
  END rw0_wd_in[121]
  PIN rw0_wd_in[122]
    DIRECTION INPUT ;
    USE SIGNAL ;
    SHAPE ABUTMENT ;
    PORT
      LAYER met2 ;
      RECT 643.010 0.000 643.150 0.420 ;
    END
  END rw0_wd_in[122]
  PIN rw0_wd_in[123]
    DIRECTION INPUT ;
    USE SIGNAL ;
    SHAPE ABUTMENT ;
    PORT
      LAYER met2 ;
      RECT 654.050 0.000 654.190 0.420 ;
    END
  END rw0_wd_in[123]
  PIN rw0_wd_in[124]
    DIRECTION INPUT ;
    USE SIGNAL ;
    SHAPE ABUTMENT ;
    PORT
      LAYER met2 ;
      RECT 665.090 0.000 665.230 0.420 ;
    END
  END rw0_wd_in[124]
  PIN rw0_wd_in[125]
    DIRECTION INPUT ;
    USE SIGNAL ;
    SHAPE ABUTMENT ;
    PORT
      LAYER met2 ;
      RECT 676.130 0.000 676.270 0.420 ;
    END
  END rw0_wd_in[125]
  PIN rw0_wd_in[126]
    DIRECTION INPUT ;
    USE SIGNAL ;
    SHAPE ABUTMENT ;
    PORT
      LAYER met2 ;
      RECT 687.170 0.000 687.310 0.420 ;
    END
  END rw0_wd_in[126]
  PIN rw0_wd_in[127]
    DIRECTION INPUT ;
    USE SIGNAL ;
    SHAPE ABUTMENT ;
    PORT
      LAYER met2 ;
      RECT 698.210 0.000 698.350 0.420 ;
    END
  END rw0_wd_in[127]
  PIN rw0_rd_out[0]
    DIRECTION OUTPUT ;
    USE SIGNAL ;
    SHAPE ABUTMENT ;
    PORT
      LAYER met2 ;
      RECT 709.250 0.000 709.390 0.420 ;
    END
  END rw0_rd_out[0]
  PIN rw0_rd_out[1]
    DIRECTION OUTPUT ;
    USE SIGNAL ;
    SHAPE ABUTMENT ;
    PORT
      LAYER met2 ;
      RECT 720.290 0.000 720.430 0.420 ;
    END
  END rw0_rd_out[1]
  PIN rw0_rd_out[2]
    DIRECTION OUTPUT ;
    USE SIGNAL ;
    SHAPE ABUTMENT ;
    PORT
      LAYER met2 ;
      RECT 731.330 0.000 731.470 0.420 ;
    END
  END rw0_rd_out[2]
  PIN rw0_rd_out[3]
    DIRECTION OUTPUT ;
    USE SIGNAL ;
    SHAPE ABUTMENT ;
    PORT
      LAYER met2 ;
      RECT 742.370 0.000 742.510 0.420 ;
    END
  END rw0_rd_out[3]
  PIN rw0_rd_out[4]
    DIRECTION OUTPUT ;
    USE SIGNAL ;
    SHAPE ABUTMENT ;
    PORT
      LAYER met2 ;
      RECT 753.410 0.000 753.550 0.420 ;
    END
  END rw0_rd_out[4]
  PIN rw0_rd_out[5]
    DIRECTION OUTPUT ;
    USE SIGNAL ;
    SHAPE ABUTMENT ;
    PORT
      LAYER met2 ;
      RECT 764.450 0.000 764.590 0.420 ;
    END
  END rw0_rd_out[5]
  PIN rw0_rd_out[6]
    DIRECTION OUTPUT ;
    USE SIGNAL ;
    SHAPE ABUTMENT ;
    PORT
      LAYER met2 ;
      RECT 775.490 0.000 775.630 0.420 ;
    END
  END rw0_rd_out[6]
  PIN rw0_rd_out[7]
    DIRECTION OUTPUT ;
    USE SIGNAL ;
    SHAPE ABUTMENT ;
    PORT
      LAYER met2 ;
      RECT 786.530 0.000 786.670 0.420 ;
    END
  END rw0_rd_out[7]
  PIN rw0_rd_out[8]
    DIRECTION OUTPUT ;
    USE SIGNAL ;
    SHAPE ABUTMENT ;
    PORT
      LAYER met2 ;
      RECT 797.570 0.000 797.710 0.420 ;
    END
  END rw0_rd_out[8]
  PIN rw0_rd_out[9]
    DIRECTION OUTPUT ;
    USE SIGNAL ;
    SHAPE ABUTMENT ;
    PORT
      LAYER met2 ;
      RECT 808.610 0.000 808.750 0.420 ;
    END
  END rw0_rd_out[9]
  PIN rw0_rd_out[10]
    DIRECTION OUTPUT ;
    USE SIGNAL ;
    SHAPE ABUTMENT ;
    PORT
      LAYER met2 ;
      RECT 819.650 0.000 819.790 0.420 ;
    END
  END rw0_rd_out[10]
  PIN rw0_rd_out[11]
    DIRECTION OUTPUT ;
    USE SIGNAL ;
    SHAPE ABUTMENT ;
    PORT
      LAYER met2 ;
      RECT 830.690 0.000 830.830 0.420 ;
    END
  END rw0_rd_out[11]
  PIN rw0_rd_out[12]
    DIRECTION OUTPUT ;
    USE SIGNAL ;
    SHAPE ABUTMENT ;
    PORT
      LAYER met2 ;
      RECT 841.730 0.000 841.870 0.420 ;
    END
  END rw0_rd_out[12]
  PIN rw0_rd_out[13]
    DIRECTION OUTPUT ;
    USE SIGNAL ;
    SHAPE ABUTMENT ;
    PORT
      LAYER met2 ;
      RECT 852.770 0.000 852.910 0.420 ;
    END
  END rw0_rd_out[13]
  PIN rw0_rd_out[14]
    DIRECTION OUTPUT ;
    USE SIGNAL ;
    SHAPE ABUTMENT ;
    PORT
      LAYER met2 ;
      RECT 863.810 0.000 863.950 0.420 ;
    END
  END rw0_rd_out[14]
  PIN rw0_rd_out[15]
    DIRECTION OUTPUT ;
    USE SIGNAL ;
    SHAPE ABUTMENT ;
    PORT
      LAYER met2 ;
      RECT 874.850 0.000 874.990 0.420 ;
    END
  END rw0_rd_out[15]
  PIN rw0_rd_out[16]
    DIRECTION OUTPUT ;
    USE SIGNAL ;
    SHAPE ABUTMENT ;
    PORT
      LAYER met2 ;
      RECT 885.890 0.000 886.030 0.420 ;
    END
  END rw0_rd_out[16]
  PIN rw0_rd_out[17]
    DIRECTION OUTPUT ;
    USE SIGNAL ;
    SHAPE ABUTMENT ;
    PORT
      LAYER met2 ;
      RECT 896.930 0.000 897.070 0.420 ;
    END
  END rw0_rd_out[17]
  PIN rw0_rd_out[18]
    DIRECTION OUTPUT ;
    USE SIGNAL ;
    SHAPE ABUTMENT ;
    PORT
      LAYER met2 ;
      RECT 907.970 0.000 908.110 0.420 ;
    END
  END rw0_rd_out[18]
  PIN rw0_rd_out[19]
    DIRECTION OUTPUT ;
    USE SIGNAL ;
    SHAPE ABUTMENT ;
    PORT
      LAYER met2 ;
      RECT 919.010 0.000 919.150 0.420 ;
    END
  END rw0_rd_out[19]
  PIN rw0_rd_out[20]
    DIRECTION OUTPUT ;
    USE SIGNAL ;
    SHAPE ABUTMENT ;
    PORT
      LAYER met2 ;
      RECT 930.050 0.000 930.190 0.420 ;
    END
  END rw0_rd_out[20]
  PIN rw0_rd_out[21]
    DIRECTION OUTPUT ;
    USE SIGNAL ;
    SHAPE ABUTMENT ;
    PORT
      LAYER met2 ;
      RECT 941.090 0.000 941.230 0.420 ;
    END
  END rw0_rd_out[21]
  PIN rw0_rd_out[22]
    DIRECTION OUTPUT ;
    USE SIGNAL ;
    SHAPE ABUTMENT ;
    PORT
      LAYER met2 ;
      RECT 952.130 0.000 952.270 0.420 ;
    END
  END rw0_rd_out[22]
  PIN rw0_rd_out[23]
    DIRECTION OUTPUT ;
    USE SIGNAL ;
    SHAPE ABUTMENT ;
    PORT
      LAYER met2 ;
      RECT 963.170 0.000 963.310 0.420 ;
    END
  END rw0_rd_out[23]
  PIN rw0_rd_out[24]
    DIRECTION OUTPUT ;
    USE SIGNAL ;
    SHAPE ABUTMENT ;
    PORT
      LAYER met2 ;
      RECT 974.210 0.000 974.350 0.420 ;
    END
  END rw0_rd_out[24]
  PIN rw0_rd_out[25]
    DIRECTION OUTPUT ;
    USE SIGNAL ;
    SHAPE ABUTMENT ;
    PORT
      LAYER met2 ;
      RECT 985.250 0.000 985.390 0.420 ;
    END
  END rw0_rd_out[25]
  PIN rw0_rd_out[26]
    DIRECTION OUTPUT ;
    USE SIGNAL ;
    SHAPE ABUTMENT ;
    PORT
      LAYER met2 ;
      RECT 996.290 0.000 996.430 0.420 ;
    END
  END rw0_rd_out[26]
  PIN rw0_rd_out[27]
    DIRECTION OUTPUT ;
    USE SIGNAL ;
    SHAPE ABUTMENT ;
    PORT
      LAYER met2 ;
      RECT 1007.330 0.000 1007.470 0.420 ;
    END
  END rw0_rd_out[27]
  PIN rw0_rd_out[28]
    DIRECTION OUTPUT ;
    USE SIGNAL ;
    SHAPE ABUTMENT ;
    PORT
      LAYER met2 ;
      RECT 1018.370 0.000 1018.510 0.420 ;
    END
  END rw0_rd_out[28]
  PIN rw0_rd_out[29]
    DIRECTION OUTPUT ;
    USE SIGNAL ;
    SHAPE ABUTMENT ;
    PORT
      LAYER met2 ;
      RECT 1029.410 0.000 1029.550 0.420 ;
    END
  END rw0_rd_out[29]
  PIN rw0_rd_out[30]
    DIRECTION OUTPUT ;
    USE SIGNAL ;
    SHAPE ABUTMENT ;
    PORT
      LAYER met2 ;
      RECT 1040.450 0.000 1040.590 0.420 ;
    END
  END rw0_rd_out[30]
  PIN rw0_rd_out[31]
    DIRECTION OUTPUT ;
    USE SIGNAL ;
    SHAPE ABUTMENT ;
    PORT
      LAYER met2 ;
      RECT 1051.490 0.000 1051.630 0.420 ;
    END
  END rw0_rd_out[31]
  PIN rw0_rd_out[32]
    DIRECTION OUTPUT ;
    USE SIGNAL ;
    SHAPE ABUTMENT ;
    PORT
      LAYER met2 ;
      RECT 1062.530 0.000 1062.670 0.420 ;
    END
  END rw0_rd_out[32]
  PIN rw0_rd_out[33]
    DIRECTION OUTPUT ;
    USE SIGNAL ;
    SHAPE ABUTMENT ;
    PORT
      LAYER met2 ;
      RECT 1073.570 0.000 1073.710 0.420 ;
    END
  END rw0_rd_out[33]
  PIN rw0_rd_out[34]
    DIRECTION OUTPUT ;
    USE SIGNAL ;
    SHAPE ABUTMENT ;
    PORT
      LAYER met2 ;
      RECT 1084.610 0.000 1084.750 0.420 ;
    END
  END rw0_rd_out[34]
  PIN rw0_rd_out[35]
    DIRECTION OUTPUT ;
    USE SIGNAL ;
    SHAPE ABUTMENT ;
    PORT
      LAYER met2 ;
      RECT 1095.650 0.000 1095.790 0.420 ;
    END
  END rw0_rd_out[35]
  PIN rw0_rd_out[36]
    DIRECTION OUTPUT ;
    USE SIGNAL ;
    SHAPE ABUTMENT ;
    PORT
      LAYER met2 ;
      RECT 1106.690 0.000 1106.830 0.420 ;
    END
  END rw0_rd_out[36]
  PIN rw0_rd_out[37]
    DIRECTION OUTPUT ;
    USE SIGNAL ;
    SHAPE ABUTMENT ;
    PORT
      LAYER met2 ;
      RECT 1117.730 0.000 1117.870 0.420 ;
    END
  END rw0_rd_out[37]
  PIN rw0_rd_out[38]
    DIRECTION OUTPUT ;
    USE SIGNAL ;
    SHAPE ABUTMENT ;
    PORT
      LAYER met2 ;
      RECT 1128.770 0.000 1128.910 0.420 ;
    END
  END rw0_rd_out[38]
  PIN rw0_rd_out[39]
    DIRECTION OUTPUT ;
    USE SIGNAL ;
    SHAPE ABUTMENT ;
    PORT
      LAYER met2 ;
      RECT 1139.810 0.000 1139.950 0.420 ;
    END
  END rw0_rd_out[39]
  PIN rw0_rd_out[40]
    DIRECTION OUTPUT ;
    USE SIGNAL ;
    SHAPE ABUTMENT ;
    PORT
      LAYER met2 ;
      RECT 1150.850 0.000 1150.990 0.420 ;
    END
  END rw0_rd_out[40]
  PIN rw0_rd_out[41]
    DIRECTION OUTPUT ;
    USE SIGNAL ;
    SHAPE ABUTMENT ;
    PORT
      LAYER met2 ;
      RECT 1161.890 0.000 1162.030 0.420 ;
    END
  END rw0_rd_out[41]
  PIN rw0_rd_out[42]
    DIRECTION OUTPUT ;
    USE SIGNAL ;
    SHAPE ABUTMENT ;
    PORT
      LAYER met2 ;
      RECT 1172.930 0.000 1173.070 0.420 ;
    END
  END rw0_rd_out[42]
  PIN rw0_rd_out[43]
    DIRECTION OUTPUT ;
    USE SIGNAL ;
    SHAPE ABUTMENT ;
    PORT
      LAYER met2 ;
      RECT 1183.970 0.000 1184.110 0.420 ;
    END
  END rw0_rd_out[43]
  PIN rw0_rd_out[44]
    DIRECTION OUTPUT ;
    USE SIGNAL ;
    SHAPE ABUTMENT ;
    PORT
      LAYER met2 ;
      RECT 1195.010 0.000 1195.150 0.420 ;
    END
  END rw0_rd_out[44]
  PIN rw0_rd_out[45]
    DIRECTION OUTPUT ;
    USE SIGNAL ;
    SHAPE ABUTMENT ;
    PORT
      LAYER met2 ;
      RECT 1206.050 0.000 1206.190 0.420 ;
    END
  END rw0_rd_out[45]
  PIN rw0_rd_out[46]
    DIRECTION OUTPUT ;
    USE SIGNAL ;
    SHAPE ABUTMENT ;
    PORT
      LAYER met2 ;
      RECT 1217.090 0.000 1217.230 0.420 ;
    END
  END rw0_rd_out[46]
  PIN rw0_rd_out[47]
    DIRECTION OUTPUT ;
    USE SIGNAL ;
    SHAPE ABUTMENT ;
    PORT
      LAYER met2 ;
      RECT 1228.130 0.000 1228.270 0.420 ;
    END
  END rw0_rd_out[47]
  PIN rw0_rd_out[48]
    DIRECTION OUTPUT ;
    USE SIGNAL ;
    SHAPE ABUTMENT ;
    PORT
      LAYER met2 ;
      RECT 1239.170 0.000 1239.310 0.420 ;
    END
  END rw0_rd_out[48]
  PIN rw0_rd_out[49]
    DIRECTION OUTPUT ;
    USE SIGNAL ;
    SHAPE ABUTMENT ;
    PORT
      LAYER met2 ;
      RECT 1250.210 0.000 1250.350 0.420 ;
    END
  END rw0_rd_out[49]
  PIN rw0_rd_out[50]
    DIRECTION OUTPUT ;
    USE SIGNAL ;
    SHAPE ABUTMENT ;
    PORT
      LAYER met2 ;
      RECT 1261.250 0.000 1261.390 0.420 ;
    END
  END rw0_rd_out[50]
  PIN rw0_rd_out[51]
    DIRECTION OUTPUT ;
    USE SIGNAL ;
    SHAPE ABUTMENT ;
    PORT
      LAYER met2 ;
      RECT 1272.290 0.000 1272.430 0.420 ;
    END
  END rw0_rd_out[51]
  PIN rw0_rd_out[52]
    DIRECTION OUTPUT ;
    USE SIGNAL ;
    SHAPE ABUTMENT ;
    PORT
      LAYER met2 ;
      RECT 1283.330 0.000 1283.470 0.420 ;
    END
  END rw0_rd_out[52]
  PIN rw0_rd_out[53]
    DIRECTION OUTPUT ;
    USE SIGNAL ;
    SHAPE ABUTMENT ;
    PORT
      LAYER met2 ;
      RECT 1294.370 0.000 1294.510 0.420 ;
    END
  END rw0_rd_out[53]
  PIN rw0_rd_out[54]
    DIRECTION OUTPUT ;
    USE SIGNAL ;
    SHAPE ABUTMENT ;
    PORT
      LAYER met2 ;
      RECT 1305.410 0.000 1305.550 0.420 ;
    END
  END rw0_rd_out[54]
  PIN rw0_rd_out[55]
    DIRECTION OUTPUT ;
    USE SIGNAL ;
    SHAPE ABUTMENT ;
    PORT
      LAYER met2 ;
      RECT 1316.450 0.000 1316.590 0.420 ;
    END
  END rw0_rd_out[55]
  PIN rw0_rd_out[56]
    DIRECTION OUTPUT ;
    USE SIGNAL ;
    SHAPE ABUTMENT ;
    PORT
      LAYER met2 ;
      RECT 1327.490 0.000 1327.630 0.420 ;
    END
  END rw0_rd_out[56]
  PIN rw0_rd_out[57]
    DIRECTION OUTPUT ;
    USE SIGNAL ;
    SHAPE ABUTMENT ;
    PORT
      LAYER met2 ;
      RECT 1338.530 0.000 1338.670 0.420 ;
    END
  END rw0_rd_out[57]
  PIN rw0_rd_out[58]
    DIRECTION OUTPUT ;
    USE SIGNAL ;
    SHAPE ABUTMENT ;
    PORT
      LAYER met2 ;
      RECT 1349.570 0.000 1349.710 0.420 ;
    END
  END rw0_rd_out[58]
  PIN rw0_rd_out[59]
    DIRECTION OUTPUT ;
    USE SIGNAL ;
    SHAPE ABUTMENT ;
    PORT
      LAYER met2 ;
      RECT 1360.610 0.000 1360.750 0.420 ;
    END
  END rw0_rd_out[59]
  PIN rw0_rd_out[60]
    DIRECTION OUTPUT ;
    USE SIGNAL ;
    SHAPE ABUTMENT ;
    PORT
      LAYER met2 ;
      RECT 1371.650 0.000 1371.790 0.420 ;
    END
  END rw0_rd_out[60]
  PIN rw0_rd_out[61]
    DIRECTION OUTPUT ;
    USE SIGNAL ;
    SHAPE ABUTMENT ;
    PORT
      LAYER met2 ;
      RECT 1382.690 0.000 1382.830 0.420 ;
    END
  END rw0_rd_out[61]
  PIN rw0_rd_out[62]
    DIRECTION OUTPUT ;
    USE SIGNAL ;
    SHAPE ABUTMENT ;
    PORT
      LAYER met2 ;
      RECT 1393.730 0.000 1393.870 0.420 ;
    END
  END rw0_rd_out[62]
  PIN rw0_rd_out[63]
    DIRECTION OUTPUT ;
    USE SIGNAL ;
    SHAPE ABUTMENT ;
    PORT
      LAYER met2 ;
      RECT 1404.770 0.000 1404.910 0.420 ;
    END
  END rw0_rd_out[63]
  PIN rw0_rd_out[64]
    DIRECTION OUTPUT ;
    USE SIGNAL ;
    SHAPE ABUTMENT ;
    PORT
      LAYER met2 ;
      RECT 153.570 2327.900 153.710 2328.320 ;
    END
  END rw0_rd_out[64]
  PIN rw0_rd_out[65]
    DIRECTION OUTPUT ;
    USE SIGNAL ;
    SHAPE ABUTMENT ;
    PORT
      LAYER met2 ;
      RECT 172.430 2327.900 172.570 2328.320 ;
    END
  END rw0_rd_out[65]
  PIN rw0_rd_out[66]
    DIRECTION OUTPUT ;
    USE SIGNAL ;
    SHAPE ABUTMENT ;
    PORT
      LAYER met2 ;
      RECT 191.290 2327.900 191.430 2328.320 ;
    END
  END rw0_rd_out[66]
  PIN rw0_rd_out[67]
    DIRECTION OUTPUT ;
    USE SIGNAL ;
    SHAPE ABUTMENT ;
    PORT
      LAYER met2 ;
      RECT 210.150 2327.900 210.290 2328.320 ;
    END
  END rw0_rd_out[67]
  PIN rw0_rd_out[68]
    DIRECTION OUTPUT ;
    USE SIGNAL ;
    SHAPE ABUTMENT ;
    PORT
      LAYER met2 ;
      RECT 229.010 2327.900 229.150 2328.320 ;
    END
  END rw0_rd_out[68]
  PIN rw0_rd_out[69]
    DIRECTION OUTPUT ;
    USE SIGNAL ;
    SHAPE ABUTMENT ;
    PORT
      LAYER met2 ;
      RECT 247.870 2327.900 248.010 2328.320 ;
    END
  END rw0_rd_out[69]
  PIN rw0_rd_out[70]
    DIRECTION OUTPUT ;
    USE SIGNAL ;
    SHAPE ABUTMENT ;
    PORT
      LAYER met2 ;
      RECT 266.730 2327.900 266.870 2328.320 ;
    END
  END rw0_rd_out[70]
  PIN rw0_rd_out[71]
    DIRECTION OUTPUT ;
    USE SIGNAL ;
    SHAPE ABUTMENT ;
    PORT
      LAYER met2 ;
      RECT 285.590 2327.900 285.730 2328.320 ;
    END
  END rw0_rd_out[71]
  PIN rw0_rd_out[72]
    DIRECTION OUTPUT ;
    USE SIGNAL ;
    SHAPE ABUTMENT ;
    PORT
      LAYER met2 ;
      RECT 304.450 2327.900 304.590 2328.320 ;
    END
  END rw0_rd_out[72]
  PIN rw0_rd_out[73]
    DIRECTION OUTPUT ;
    USE SIGNAL ;
    SHAPE ABUTMENT ;
    PORT
      LAYER met2 ;
      RECT 323.310 2327.900 323.450 2328.320 ;
    END
  END rw0_rd_out[73]
  PIN rw0_rd_out[74]
    DIRECTION OUTPUT ;
    USE SIGNAL ;
    SHAPE ABUTMENT ;
    PORT
      LAYER met2 ;
      RECT 342.170 2327.900 342.310 2328.320 ;
    END
  END rw0_rd_out[74]
  PIN rw0_rd_out[75]
    DIRECTION OUTPUT ;
    USE SIGNAL ;
    SHAPE ABUTMENT ;
    PORT
      LAYER met2 ;
      RECT 361.030 2327.900 361.170 2328.320 ;
    END
  END rw0_rd_out[75]
  PIN rw0_rd_out[76]
    DIRECTION OUTPUT ;
    USE SIGNAL ;
    SHAPE ABUTMENT ;
    PORT
      LAYER met2 ;
      RECT 379.890 2327.900 380.030 2328.320 ;
    END
  END rw0_rd_out[76]
  PIN rw0_rd_out[77]
    DIRECTION OUTPUT ;
    USE SIGNAL ;
    SHAPE ABUTMENT ;
    PORT
      LAYER met2 ;
      RECT 398.750 2327.900 398.890 2328.320 ;
    END
  END rw0_rd_out[77]
  PIN rw0_rd_out[78]
    DIRECTION OUTPUT ;
    USE SIGNAL ;
    SHAPE ABUTMENT ;
    PORT
      LAYER met2 ;
      RECT 417.610 2327.900 417.750 2328.320 ;
    END
  END rw0_rd_out[78]
  PIN rw0_rd_out[79]
    DIRECTION OUTPUT ;
    USE SIGNAL ;
    SHAPE ABUTMENT ;
    PORT
      LAYER met2 ;
      RECT 436.470 2327.900 436.610 2328.320 ;
    END
  END rw0_rd_out[79]
  PIN rw0_rd_out[80]
    DIRECTION OUTPUT ;
    USE SIGNAL ;
    SHAPE ABUTMENT ;
    PORT
      LAYER met2 ;
      RECT 455.330 2327.900 455.470 2328.320 ;
    END
  END rw0_rd_out[80]
  PIN rw0_rd_out[81]
    DIRECTION OUTPUT ;
    USE SIGNAL ;
    SHAPE ABUTMENT ;
    PORT
      LAYER met2 ;
      RECT 474.190 2327.900 474.330 2328.320 ;
    END
  END rw0_rd_out[81]
  PIN rw0_rd_out[82]
    DIRECTION OUTPUT ;
    USE SIGNAL ;
    SHAPE ABUTMENT ;
    PORT
      LAYER met2 ;
      RECT 493.050 2327.900 493.190 2328.320 ;
    END
  END rw0_rd_out[82]
  PIN rw0_rd_out[83]
    DIRECTION OUTPUT ;
    USE SIGNAL ;
    SHAPE ABUTMENT ;
    PORT
      LAYER met2 ;
      RECT 511.910 2327.900 512.050 2328.320 ;
    END
  END rw0_rd_out[83]
  PIN rw0_rd_out[84]
    DIRECTION OUTPUT ;
    USE SIGNAL ;
    SHAPE ABUTMENT ;
    PORT
      LAYER met2 ;
      RECT 530.770 2327.900 530.910 2328.320 ;
    END
  END rw0_rd_out[84]
  PIN rw0_rd_out[85]
    DIRECTION OUTPUT ;
    USE SIGNAL ;
    SHAPE ABUTMENT ;
    PORT
      LAYER met2 ;
      RECT 549.630 2327.900 549.770 2328.320 ;
    END
  END rw0_rd_out[85]
  PIN rw0_rd_out[86]
    DIRECTION OUTPUT ;
    USE SIGNAL ;
    SHAPE ABUTMENT ;
    PORT
      LAYER met2 ;
      RECT 568.490 2327.900 568.630 2328.320 ;
    END
  END rw0_rd_out[86]
  PIN rw0_rd_out[87]
    DIRECTION OUTPUT ;
    USE SIGNAL ;
    SHAPE ABUTMENT ;
    PORT
      LAYER met2 ;
      RECT 587.350 2327.900 587.490 2328.320 ;
    END
  END rw0_rd_out[87]
  PIN rw0_rd_out[88]
    DIRECTION OUTPUT ;
    USE SIGNAL ;
    SHAPE ABUTMENT ;
    PORT
      LAYER met2 ;
      RECT 606.210 2327.900 606.350 2328.320 ;
    END
  END rw0_rd_out[88]
  PIN rw0_rd_out[89]
    DIRECTION OUTPUT ;
    USE SIGNAL ;
    SHAPE ABUTMENT ;
    PORT
      LAYER met2 ;
      RECT 625.070 2327.900 625.210 2328.320 ;
    END
  END rw0_rd_out[89]
  PIN rw0_rd_out[90]
    DIRECTION OUTPUT ;
    USE SIGNAL ;
    SHAPE ABUTMENT ;
    PORT
      LAYER met2 ;
      RECT 643.930 2327.900 644.070 2328.320 ;
    END
  END rw0_rd_out[90]
  PIN rw0_rd_out[91]
    DIRECTION OUTPUT ;
    USE SIGNAL ;
    SHAPE ABUTMENT ;
    PORT
      LAYER met2 ;
      RECT 662.790 2327.900 662.930 2328.320 ;
    END
  END rw0_rd_out[91]
  PIN rw0_rd_out[92]
    DIRECTION OUTPUT ;
    USE SIGNAL ;
    SHAPE ABUTMENT ;
    PORT
      LAYER met2 ;
      RECT 681.650 2327.900 681.790 2328.320 ;
    END
  END rw0_rd_out[92]
  PIN rw0_rd_out[93]
    DIRECTION OUTPUT ;
    USE SIGNAL ;
    SHAPE ABUTMENT ;
    PORT
      LAYER met2 ;
      RECT 700.510 2327.900 700.650 2328.320 ;
    END
  END rw0_rd_out[93]
  PIN rw0_rd_out[94]
    DIRECTION OUTPUT ;
    USE SIGNAL ;
    SHAPE ABUTMENT ;
    PORT
      LAYER met2 ;
      RECT 719.370 2327.900 719.510 2328.320 ;
    END
  END rw0_rd_out[94]
  PIN rw0_rd_out[95]
    DIRECTION OUTPUT ;
    USE SIGNAL ;
    SHAPE ABUTMENT ;
    PORT
      LAYER met2 ;
      RECT 738.230 2327.900 738.370 2328.320 ;
    END
  END rw0_rd_out[95]
  PIN rw0_rd_out[96]
    DIRECTION OUTPUT ;
    USE SIGNAL ;
    SHAPE ABUTMENT ;
    PORT
      LAYER met2 ;
      RECT 757.090 2327.900 757.230 2328.320 ;
    END
  END rw0_rd_out[96]
  PIN rw0_rd_out[97]
    DIRECTION OUTPUT ;
    USE SIGNAL ;
    SHAPE ABUTMENT ;
    PORT
      LAYER met2 ;
      RECT 775.950 2327.900 776.090 2328.320 ;
    END
  END rw0_rd_out[97]
  PIN rw0_rd_out[98]
    DIRECTION OUTPUT ;
    USE SIGNAL ;
    SHAPE ABUTMENT ;
    PORT
      LAYER met2 ;
      RECT 794.810 2327.900 794.950 2328.320 ;
    END
  END rw0_rd_out[98]
  PIN rw0_rd_out[99]
    DIRECTION OUTPUT ;
    USE SIGNAL ;
    SHAPE ABUTMENT ;
    PORT
      LAYER met2 ;
      RECT 813.670 2327.900 813.810 2328.320 ;
    END
  END rw0_rd_out[99]
  PIN rw0_rd_out[100]
    DIRECTION OUTPUT ;
    USE SIGNAL ;
    SHAPE ABUTMENT ;
    PORT
      LAYER met2 ;
      RECT 832.530 2327.900 832.670 2328.320 ;
    END
  END rw0_rd_out[100]
  PIN rw0_rd_out[101]
    DIRECTION OUTPUT ;
    USE SIGNAL ;
    SHAPE ABUTMENT ;
    PORT
      LAYER met2 ;
      RECT 851.390 2327.900 851.530 2328.320 ;
    END
  END rw0_rd_out[101]
  PIN rw0_rd_out[102]
    DIRECTION OUTPUT ;
    USE SIGNAL ;
    SHAPE ABUTMENT ;
    PORT
      LAYER met2 ;
      RECT 870.250 2327.900 870.390 2328.320 ;
    END
  END rw0_rd_out[102]
  PIN rw0_rd_out[103]
    DIRECTION OUTPUT ;
    USE SIGNAL ;
    SHAPE ABUTMENT ;
    PORT
      LAYER met2 ;
      RECT 889.110 2327.900 889.250 2328.320 ;
    END
  END rw0_rd_out[103]
  PIN rw0_rd_out[104]
    DIRECTION OUTPUT ;
    USE SIGNAL ;
    SHAPE ABUTMENT ;
    PORT
      LAYER met2 ;
      RECT 907.970 2327.900 908.110 2328.320 ;
    END
  END rw0_rd_out[104]
  PIN rw0_rd_out[105]
    DIRECTION OUTPUT ;
    USE SIGNAL ;
    SHAPE ABUTMENT ;
    PORT
      LAYER met2 ;
      RECT 926.830 2327.900 926.970 2328.320 ;
    END
  END rw0_rd_out[105]
  PIN rw0_rd_out[106]
    DIRECTION OUTPUT ;
    USE SIGNAL ;
    SHAPE ABUTMENT ;
    PORT
      LAYER met2 ;
      RECT 945.690 2327.900 945.830 2328.320 ;
    END
  END rw0_rd_out[106]
  PIN rw0_rd_out[107]
    DIRECTION OUTPUT ;
    USE SIGNAL ;
    SHAPE ABUTMENT ;
    PORT
      LAYER met2 ;
      RECT 964.550 2327.900 964.690 2328.320 ;
    END
  END rw0_rd_out[107]
  PIN rw0_rd_out[108]
    DIRECTION OUTPUT ;
    USE SIGNAL ;
    SHAPE ABUTMENT ;
    PORT
      LAYER met2 ;
      RECT 983.410 2327.900 983.550 2328.320 ;
    END
  END rw0_rd_out[108]
  PIN rw0_rd_out[109]
    DIRECTION OUTPUT ;
    USE SIGNAL ;
    SHAPE ABUTMENT ;
    PORT
      LAYER met2 ;
      RECT 1002.270 2327.900 1002.410 2328.320 ;
    END
  END rw0_rd_out[109]
  PIN rw0_rd_out[110]
    DIRECTION OUTPUT ;
    USE SIGNAL ;
    SHAPE ABUTMENT ;
    PORT
      LAYER met2 ;
      RECT 1021.130 2327.900 1021.270 2328.320 ;
    END
  END rw0_rd_out[110]
  PIN rw0_rd_out[111]
    DIRECTION OUTPUT ;
    USE SIGNAL ;
    SHAPE ABUTMENT ;
    PORT
      LAYER met2 ;
      RECT 1039.990 2327.900 1040.130 2328.320 ;
    END
  END rw0_rd_out[111]
  PIN rw0_rd_out[112]
    DIRECTION OUTPUT ;
    USE SIGNAL ;
    SHAPE ABUTMENT ;
    PORT
      LAYER met2 ;
      RECT 1058.850 2327.900 1058.990 2328.320 ;
    END
  END rw0_rd_out[112]
  PIN rw0_rd_out[113]
    DIRECTION OUTPUT ;
    USE SIGNAL ;
    SHAPE ABUTMENT ;
    PORT
      LAYER met2 ;
      RECT 1077.710 2327.900 1077.850 2328.320 ;
    END
  END rw0_rd_out[113]
  PIN rw0_rd_out[114]
    DIRECTION OUTPUT ;
    USE SIGNAL ;
    SHAPE ABUTMENT ;
    PORT
      LAYER met2 ;
      RECT 1096.570 2327.900 1096.710 2328.320 ;
    END
  END rw0_rd_out[114]
  PIN rw0_rd_out[115]
    DIRECTION OUTPUT ;
    USE SIGNAL ;
    SHAPE ABUTMENT ;
    PORT
      LAYER met2 ;
      RECT 1115.430 2327.900 1115.570 2328.320 ;
    END
  END rw0_rd_out[115]
  PIN rw0_rd_out[116]
    DIRECTION OUTPUT ;
    USE SIGNAL ;
    SHAPE ABUTMENT ;
    PORT
      LAYER met2 ;
      RECT 1134.290 2327.900 1134.430 2328.320 ;
    END
  END rw0_rd_out[116]
  PIN rw0_rd_out[117]
    DIRECTION OUTPUT ;
    USE SIGNAL ;
    SHAPE ABUTMENT ;
    PORT
      LAYER met2 ;
      RECT 1153.150 2327.900 1153.290 2328.320 ;
    END
  END rw0_rd_out[117]
  PIN rw0_rd_out[118]
    DIRECTION OUTPUT ;
    USE SIGNAL ;
    SHAPE ABUTMENT ;
    PORT
      LAYER met2 ;
      RECT 1172.010 2327.900 1172.150 2328.320 ;
    END
  END rw0_rd_out[118]
  PIN rw0_rd_out[119]
    DIRECTION OUTPUT ;
    USE SIGNAL ;
    SHAPE ABUTMENT ;
    PORT
      LAYER met2 ;
      RECT 1190.870 2327.900 1191.010 2328.320 ;
    END
  END rw0_rd_out[119]
  PIN rw0_rd_out[120]
    DIRECTION OUTPUT ;
    USE SIGNAL ;
    SHAPE ABUTMENT ;
    PORT
      LAYER met2 ;
      RECT 1209.730 2327.900 1209.870 2328.320 ;
    END
  END rw0_rd_out[120]
  PIN rw0_rd_out[121]
    DIRECTION OUTPUT ;
    USE SIGNAL ;
    SHAPE ABUTMENT ;
    PORT
      LAYER met2 ;
      RECT 1228.590 2327.900 1228.730 2328.320 ;
    END
  END rw0_rd_out[121]
  PIN rw0_rd_out[122]
    DIRECTION OUTPUT ;
    USE SIGNAL ;
    SHAPE ABUTMENT ;
    PORT
      LAYER met2 ;
      RECT 1247.450 2327.900 1247.590 2328.320 ;
    END
  END rw0_rd_out[122]
  PIN rw0_rd_out[123]
    DIRECTION OUTPUT ;
    USE SIGNAL ;
    SHAPE ABUTMENT ;
    PORT
      LAYER met2 ;
      RECT 1266.310 2327.900 1266.450 2328.320 ;
    END
  END rw0_rd_out[123]
  PIN rw0_rd_out[124]
    DIRECTION OUTPUT ;
    USE SIGNAL ;
    SHAPE ABUTMENT ;
    PORT
      LAYER met2 ;
      RECT 1285.170 2327.900 1285.310 2328.320 ;
    END
  END rw0_rd_out[124]
  PIN rw0_rd_out[125]
    DIRECTION OUTPUT ;
    USE SIGNAL ;
    SHAPE ABUTMENT ;
    PORT
      LAYER met2 ;
      RECT 1304.030 2327.900 1304.170 2328.320 ;
    END
  END rw0_rd_out[125]
  PIN rw0_rd_out[126]
    DIRECTION OUTPUT ;
    USE SIGNAL ;
    SHAPE ABUTMENT ;
    PORT
      LAYER met2 ;
      RECT 1322.890 2327.900 1323.030 2328.320 ;
    END
  END rw0_rd_out[126]
  PIN rw0_rd_out[127]
    DIRECTION OUTPUT ;
    USE SIGNAL ;
    SHAPE ABUTMENT ;
    PORT
      LAYER met2 ;
      RECT 1341.750 2327.900 1341.890 2328.320 ;
    END
  END rw0_rd_out[127]
  PIN rw0_addr_in[0]
    DIRECTION INPUT ;
    USE SIGNAL ;
    SHAPE ABUTMENT ;
    PORT
      LAYER met3 ;
      RECT 0.000 1986.810 0.900 1987.110 ;
    END
  END rw0_addr_in[0]
  PIN rw0_addr_in[1]
    DIRECTION INPUT ;
    USE SIGNAL ;
    SHAPE ABUTMENT ;
    PORT
      LAYER met3 ;
      RECT 0.000 2041.890 0.900 2042.190 ;
    END
  END rw0_addr_in[1]
  PIN rw0_addr_in[2]
    DIRECTION INPUT ;
    USE SIGNAL ;
    SHAPE ABUTMENT ;
    PORT
      LAYER met3 ;
      RECT 0.000 2096.970 0.900 2097.270 ;
    END
  END rw0_addr_in[2]
  PIN rw0_addr_in[3]
    DIRECTION INPUT ;
    USE SIGNAL ;
    SHAPE ABUTMENT ;
    PORT
      LAYER met3 ;
      RECT 0.000 2152.050 0.900 2152.350 ;
    END
  END rw0_addr_in[3]
  PIN rw0_addr_in[4]
    DIRECTION INPUT ;
    USE SIGNAL ;
    SHAPE ABUTMENT ;
    PORT
      LAYER met3 ;
      RECT 0.000 2207.130 0.900 2207.430 ;
    END
  END rw0_addr_in[4]
  PIN rw0_addr_in[5]
    DIRECTION INPUT ;
    USE SIGNAL ;
    SHAPE ABUTMENT ;
    PORT
      LAYER met3 ;
      RECT 0.000 2262.210 0.900 2262.510 ;
    END
  END rw0_addr_in[5]
  PIN rw0_addr_in[6]
    DIRECTION INPUT ;
    USE SIGNAL ;
    SHAPE ABUTMENT ;
    PORT
      LAYER met3 ;
      RECT 1430.620 1986.810 1431.520 1987.110 ;
    END
  END rw0_addr_in[6]
  PIN rw0_addr_in[7]
    DIRECTION INPUT ;
    USE SIGNAL ;
    SHAPE ABUTMENT ;
    PORT
      LAYER met3 ;
      RECT 1430.620 2041.890 1431.520 2042.190 ;
    END
  END rw0_addr_in[7]
  PIN rw0_addr_in[8]
    DIRECTION INPUT ;
    USE SIGNAL ;
    SHAPE ABUTMENT ;
    PORT
      LAYER met3 ;
      RECT 1430.620 2096.970 1431.520 2097.270 ;
    END
  END rw0_addr_in[8]
  PIN rw0_addr_in[9]
    DIRECTION INPUT ;
    USE SIGNAL ;
    SHAPE ABUTMENT ;
    PORT
      LAYER met3 ;
      RECT 1430.620 2152.050 1431.520 2152.350 ;
    END
  END rw0_addr_in[9]
  PIN rw0_addr_in[10]
    DIRECTION INPUT ;
    USE SIGNAL ;
    SHAPE ABUTMENT ;
    PORT
      LAYER met3 ;
      RECT 1430.620 2207.130 1431.520 2207.430 ;
    END
  END rw0_addr_in[10]
  PIN rw0_we_in
    DIRECTION INPUT ;
    USE SIGNAL ;
    SHAPE ABUTMENT ;
    PORT
      LAYER met2 ;
      RECT 1360.610 2327.900 1360.750 2328.320 ;
    END
  END rw0_we_in
  PIN rw0_ce_in
    DIRECTION INPUT ;
    USE SIGNAL ;
    SHAPE ABUTMENT ;
    PORT
      LAYER met2 ;
      RECT 1379.470 2327.900 1379.610 2328.320 ;
    END
  END rw0_ce_in
  PIN rw0_clk
    DIRECTION INPUT ;
    USE SIGNAL ;
    SHAPE ABUTMENT ;
    PORT
      LAYER met2 ;
      RECT 1398.330 2327.900 1398.470 2328.320 ;
    END
  END rw0_clk
  PIN VSS
    DIRECTION INOUT ;
    USE GROUND ;
    PORT
      LAYER met4 ;
      RECT 2.160 4.080 3.360 2324.240 ;
      RECT 13.040 4.080 14.240 2324.240 ;
      RECT 23.920 4.080 25.120 2324.240 ;
      RECT 34.800 4.080 36.000 2324.240 ;
      RECT 45.680 4.080 46.880 2324.240 ;
      RECT 56.560 4.080 57.760 2324.240 ;
      RECT 67.440 4.080 68.640 2324.240 ;
      RECT 78.320 4.080 79.520 2324.240 ;
      RECT 89.200 4.080 90.400 2324.240 ;
      RECT 100.080 4.080 101.280 2324.240 ;
      RECT 110.960 4.080 112.160 2324.240 ;
      RECT 121.840 4.080 123.040 2324.240 ;
      RECT 132.720 4.080 133.920 2324.240 ;
      RECT 143.600 4.080 144.800 2324.240 ;
      RECT 154.480 4.080 155.680 2324.240 ;
      RECT 165.360 4.080 166.560 2324.240 ;
      RECT 176.240 4.080 177.440 2324.240 ;
      RECT 187.120 4.080 188.320 2324.240 ;
      RECT 198.000 4.080 199.200 2324.240 ;
      RECT 208.880 4.080 210.080 2324.240 ;
      RECT 219.760 4.080 220.960 2324.240 ;
      RECT 230.640 4.080 231.840 2324.240 ;
      RECT 241.520 4.080 242.720 2324.240 ;
      RECT 252.400 4.080 253.600 2324.240 ;
      RECT 263.280 4.080 264.480 2324.240 ;
      RECT 274.160 4.080 275.360 2324.240 ;
      RECT 285.040 4.080 286.240 2324.240 ;
      RECT 295.920 4.080 297.120 2324.240 ;
      RECT 306.800 4.080 308.000 2324.240 ;
      RECT 317.680 4.080 318.880 2324.240 ;
      RECT 328.560 4.080 329.760 2324.240 ;
      RECT 339.440 4.080 340.640 2324.240 ;
      RECT 350.320 4.080 351.520 2324.240 ;
      RECT 361.200 4.080 362.400 2324.240 ;
      RECT 372.080 4.080 373.280 2324.240 ;
      RECT 382.960 4.080 384.160 2324.240 ;
      RECT 393.840 4.080 395.040 2324.240 ;
      RECT 404.720 4.080 405.920 2324.240 ;
      RECT 415.600 4.080 416.800 2324.240 ;
      RECT 426.480 4.080 427.680 2324.240 ;
      RECT 437.360 4.080 438.560 2324.240 ;
      RECT 448.240 4.080 449.440 2324.240 ;
      RECT 459.120 4.080 460.320 2324.240 ;
      RECT 470.000 4.080 471.200 2324.240 ;
      RECT 480.880 4.080 482.080 2324.240 ;
      RECT 491.760 4.080 492.960 2324.240 ;
      RECT 502.640 4.080 503.840 2324.240 ;
      RECT 513.520 4.080 514.720 2324.240 ;
      RECT 524.400 4.080 525.600 2324.240 ;
      RECT 535.280 4.080 536.480 2324.240 ;
      RECT 546.160 4.080 547.360 2324.240 ;
      RECT 557.040 4.080 558.240 2324.240 ;
      RECT 567.920 4.080 569.120 2324.240 ;
      RECT 578.800 4.080 580.000 2324.240 ;
      RECT 589.680 4.080 590.880 2324.240 ;
      RECT 600.560 4.080 601.760 2324.240 ;
      RECT 611.440 4.080 612.640 2324.240 ;
      RECT 622.320 4.080 623.520 2324.240 ;
      RECT 633.200 4.080 634.400 2324.240 ;
      RECT 644.080 4.080 645.280 2324.240 ;
      RECT 654.960 4.080 656.160 2324.240 ;
      RECT 665.840 4.080 667.040 2324.240 ;
      RECT 676.720 4.080 677.920 2324.240 ;
      RECT 687.600 4.080 688.800 2324.240 ;
      RECT 698.480 4.080 699.680 2324.240 ;
      RECT 709.360 4.080 710.560 2324.240 ;
      RECT 720.240 4.080 721.440 2324.240 ;
      RECT 731.120 4.080 732.320 2324.240 ;
      RECT 742.000 4.080 743.200 2324.240 ;
      RECT 752.880 4.080 754.080 2324.240 ;
      RECT 763.760 4.080 764.960 2324.240 ;
      RECT 774.640 4.080 775.840 2324.240 ;
      RECT 785.520 4.080 786.720 2324.240 ;
      RECT 796.400 4.080 797.600 2324.240 ;
      RECT 807.280 4.080 808.480 2324.240 ;
      RECT 818.160 4.080 819.360 2324.240 ;
      RECT 829.040 4.080 830.240 2324.240 ;
      RECT 839.920 4.080 841.120 2324.240 ;
      RECT 850.800 4.080 852.000 2324.240 ;
      RECT 861.680 4.080 862.880 2324.240 ;
      RECT 872.560 4.080 873.760 2324.240 ;
      RECT 883.440 4.080 884.640 2324.240 ;
      RECT 894.320 4.080 895.520 2324.240 ;
      RECT 905.200 4.080 906.400 2324.240 ;
      RECT 916.080 4.080 917.280 2324.240 ;
      RECT 926.960 4.080 928.160 2324.240 ;
      RECT 937.840 4.080 939.040 2324.240 ;
      RECT 948.720 4.080 949.920 2324.240 ;
      RECT 959.600 4.080 960.800 2324.240 ;
      RECT 970.480 4.080 971.680 2324.240 ;
      RECT 981.360 4.080 982.560 2324.240 ;
      RECT 992.240 4.080 993.440 2324.240 ;
      RECT 1003.120 4.080 1004.320 2324.240 ;
      RECT 1014.000 4.080 1015.200 2324.240 ;
      RECT 1024.880 4.080 1026.080 2324.240 ;
      RECT 1035.760 4.080 1036.960 2324.240 ;
      RECT 1046.640 4.080 1047.840 2324.240 ;
      RECT 1057.520 4.080 1058.720 2324.240 ;
      RECT 1068.400 4.080 1069.600 2324.240 ;
      RECT 1079.280 4.080 1080.480 2324.240 ;
      RECT 1090.160 4.080 1091.360 2324.240 ;
      RECT 1101.040 4.080 1102.240 2324.240 ;
      RECT 1111.920 4.080 1113.120 2324.240 ;
      RECT 1122.800 4.080 1124.000 2324.240 ;
      RECT 1133.680 4.080 1134.880 2324.240 ;
      RECT 1144.560 4.080 1145.760 2324.240 ;
      RECT 1155.440 4.080 1156.640 2324.240 ;
      RECT 1166.320 4.080 1167.520 2324.240 ;
      RECT 1177.200 4.080 1178.400 2324.240 ;
      RECT 1188.080 4.080 1189.280 2324.240 ;
      RECT 1198.960 4.080 1200.160 2324.240 ;
      RECT 1209.840 4.080 1211.040 2324.240 ;
      RECT 1220.720 4.080 1221.920 2324.240 ;
      RECT 1231.600 4.080 1232.800 2324.240 ;
      RECT 1242.480 4.080 1243.680 2324.240 ;
      RECT 1253.360 4.080 1254.560 2324.240 ;
      RECT 1264.240 4.080 1265.440 2324.240 ;
      RECT 1275.120 4.080 1276.320 2324.240 ;
      RECT 1286.000 4.080 1287.200 2324.240 ;
      RECT 1296.880 4.080 1298.080 2324.240 ;
      RECT 1307.760 4.080 1308.960 2324.240 ;
      RECT 1318.640 4.080 1319.840 2324.240 ;
      RECT 1329.520 4.080 1330.720 2324.240 ;
      RECT 1340.400 4.080 1341.600 2324.240 ;
      RECT 1351.280 4.080 1352.480 2324.240 ;
      RECT 1362.160 4.080 1363.360 2324.240 ;
      RECT 1373.040 4.080 1374.240 2324.240 ;
      RECT 1383.920 4.080 1385.120 2324.240 ;
      RECT 1394.800 4.080 1396.000 2324.240 ;
      RECT 1405.680 4.080 1406.880 2324.240 ;
      RECT 1416.560 4.080 1417.760 2324.240 ;
      RECT 1427.440 4.080 1428.640 2324.240 ;
    END
  END VSS
  PIN VDD
    DIRECTION INOUT ;
    USE POWER ;
    PORT
      LAYER met4 ;
      RECT 7.600 4.080 8.800 2324.240 ;
      RECT 18.480 4.080 19.680 2324.240 ;
      RECT 29.360 4.080 30.560 2324.240 ;
      RECT 40.240 4.080 41.440 2324.240 ;
      RECT 51.120 4.080 52.320 2324.240 ;
      RECT 62.000 4.080 63.200 2324.240 ;
      RECT 72.880 4.080 74.080 2324.240 ;
      RECT 83.760 4.080 84.960 2324.240 ;
      RECT 94.640 4.080 95.840 2324.240 ;
      RECT 105.520 4.080 106.720 2324.240 ;
      RECT 116.400 4.080 117.600 2324.240 ;
      RECT 127.280 4.080 128.480 2324.240 ;
      RECT 138.160 4.080 139.360 2324.240 ;
      RECT 149.040 4.080 150.240 2324.240 ;
      RECT 159.920 4.080 161.120 2324.240 ;
      RECT 170.800 4.080 172.000 2324.240 ;
      RECT 181.680 4.080 182.880 2324.240 ;
      RECT 192.560 4.080 193.760 2324.240 ;
      RECT 203.440 4.080 204.640 2324.240 ;
      RECT 214.320 4.080 215.520 2324.240 ;
      RECT 225.200 4.080 226.400 2324.240 ;
      RECT 236.080 4.080 237.280 2324.240 ;
      RECT 246.960 4.080 248.160 2324.240 ;
      RECT 257.840 4.080 259.040 2324.240 ;
      RECT 268.720 4.080 269.920 2324.240 ;
      RECT 279.600 4.080 280.800 2324.240 ;
      RECT 290.480 4.080 291.680 2324.240 ;
      RECT 301.360 4.080 302.560 2324.240 ;
      RECT 312.240 4.080 313.440 2324.240 ;
      RECT 323.120 4.080 324.320 2324.240 ;
      RECT 334.000 4.080 335.200 2324.240 ;
      RECT 344.880 4.080 346.080 2324.240 ;
      RECT 355.760 4.080 356.960 2324.240 ;
      RECT 366.640 4.080 367.840 2324.240 ;
      RECT 377.520 4.080 378.720 2324.240 ;
      RECT 388.400 4.080 389.600 2324.240 ;
      RECT 399.280 4.080 400.480 2324.240 ;
      RECT 410.160 4.080 411.360 2324.240 ;
      RECT 421.040 4.080 422.240 2324.240 ;
      RECT 431.920 4.080 433.120 2324.240 ;
      RECT 442.800 4.080 444.000 2324.240 ;
      RECT 453.680 4.080 454.880 2324.240 ;
      RECT 464.560 4.080 465.760 2324.240 ;
      RECT 475.440 4.080 476.640 2324.240 ;
      RECT 486.320 4.080 487.520 2324.240 ;
      RECT 497.200 4.080 498.400 2324.240 ;
      RECT 508.080 4.080 509.280 2324.240 ;
      RECT 518.960 4.080 520.160 2324.240 ;
      RECT 529.840 4.080 531.040 2324.240 ;
      RECT 540.720 4.080 541.920 2324.240 ;
      RECT 551.600 4.080 552.800 2324.240 ;
      RECT 562.480 4.080 563.680 2324.240 ;
      RECT 573.360 4.080 574.560 2324.240 ;
      RECT 584.240 4.080 585.440 2324.240 ;
      RECT 595.120 4.080 596.320 2324.240 ;
      RECT 606.000 4.080 607.200 2324.240 ;
      RECT 616.880 4.080 618.080 2324.240 ;
      RECT 627.760 4.080 628.960 2324.240 ;
      RECT 638.640 4.080 639.840 2324.240 ;
      RECT 649.520 4.080 650.720 2324.240 ;
      RECT 660.400 4.080 661.600 2324.240 ;
      RECT 671.280 4.080 672.480 2324.240 ;
      RECT 682.160 4.080 683.360 2324.240 ;
      RECT 693.040 4.080 694.240 2324.240 ;
      RECT 703.920 4.080 705.120 2324.240 ;
      RECT 714.800 4.080 716.000 2324.240 ;
      RECT 725.680 4.080 726.880 2324.240 ;
      RECT 736.560 4.080 737.760 2324.240 ;
      RECT 747.440 4.080 748.640 2324.240 ;
      RECT 758.320 4.080 759.520 2324.240 ;
      RECT 769.200 4.080 770.400 2324.240 ;
      RECT 780.080 4.080 781.280 2324.240 ;
      RECT 790.960 4.080 792.160 2324.240 ;
      RECT 801.840 4.080 803.040 2324.240 ;
      RECT 812.720 4.080 813.920 2324.240 ;
      RECT 823.600 4.080 824.800 2324.240 ;
      RECT 834.480 4.080 835.680 2324.240 ;
      RECT 845.360 4.080 846.560 2324.240 ;
      RECT 856.240 4.080 857.440 2324.240 ;
      RECT 867.120 4.080 868.320 2324.240 ;
      RECT 878.000 4.080 879.200 2324.240 ;
      RECT 888.880 4.080 890.080 2324.240 ;
      RECT 899.760 4.080 900.960 2324.240 ;
      RECT 910.640 4.080 911.840 2324.240 ;
      RECT 921.520 4.080 922.720 2324.240 ;
      RECT 932.400 4.080 933.600 2324.240 ;
      RECT 943.280 4.080 944.480 2324.240 ;
      RECT 954.160 4.080 955.360 2324.240 ;
      RECT 965.040 4.080 966.240 2324.240 ;
      RECT 975.920 4.080 977.120 2324.240 ;
      RECT 986.800 4.080 988.000 2324.240 ;
      RECT 997.680 4.080 998.880 2324.240 ;
      RECT 1008.560 4.080 1009.760 2324.240 ;
      RECT 1019.440 4.080 1020.640 2324.240 ;
      RECT 1030.320 4.080 1031.520 2324.240 ;
      RECT 1041.200 4.080 1042.400 2324.240 ;
      RECT 1052.080 4.080 1053.280 2324.240 ;
      RECT 1062.960 4.080 1064.160 2324.240 ;
      RECT 1073.840 4.080 1075.040 2324.240 ;
      RECT 1084.720 4.080 1085.920 2324.240 ;
      RECT 1095.600 4.080 1096.800 2324.240 ;
      RECT 1106.480 4.080 1107.680 2324.240 ;
      RECT 1117.360 4.080 1118.560 2324.240 ;
      RECT 1128.240 4.080 1129.440 2324.240 ;
      RECT 1139.120 4.080 1140.320 2324.240 ;
      RECT 1150.000 4.080 1151.200 2324.240 ;
      RECT 1160.880 4.080 1162.080 2324.240 ;
      RECT 1171.760 4.080 1172.960 2324.240 ;
      RECT 1182.640 4.080 1183.840 2324.240 ;
      RECT 1193.520 4.080 1194.720 2324.240 ;
      RECT 1204.400 4.080 1205.600 2324.240 ;
      RECT 1215.280 4.080 1216.480 2324.240 ;
      RECT 1226.160 4.080 1227.360 2324.240 ;
      RECT 1237.040 4.080 1238.240 2324.240 ;
      RECT 1247.920 4.080 1249.120 2324.240 ;
      RECT 1258.800 4.080 1260.000 2324.240 ;
      RECT 1269.680 4.080 1270.880 2324.240 ;
      RECT 1280.560 4.080 1281.760 2324.240 ;
      RECT 1291.440 4.080 1292.640 2324.240 ;
      RECT 1302.320 4.080 1303.520 2324.240 ;
      RECT 1313.200 4.080 1314.400 2324.240 ;
      RECT 1324.080 4.080 1325.280 2324.240 ;
      RECT 1334.960 4.080 1336.160 2324.240 ;
      RECT 1345.840 4.080 1347.040 2324.240 ;
      RECT 1356.720 4.080 1357.920 2324.240 ;
      RECT 1367.600 4.080 1368.800 2324.240 ;
      RECT 1378.480 4.080 1379.680 2324.240 ;
      RECT 1389.360 4.080 1390.560 2324.240 ;
      RECT 1400.240 4.080 1401.440 2324.240 ;
      RECT 1411.120 4.080 1412.320 2324.240 ;
      RECT 1422.000 4.080 1423.200 2324.240 ;
    END
  END VDD
  OBS
    LAYER met1 ;
    RECT 0 0 1431.520 2328.320 ;
    LAYER met2 ;
    RECT 0 0 1431.520 2328.320 ;
    LAYER met3 ;
    RECT 0 0 1431.520 2328.320 ;
    LAYER met4 ;
    RECT 0 0 1431.520 2328.320 ;
  END
END fakeram_2048x128_1rw

END LIBRARY
